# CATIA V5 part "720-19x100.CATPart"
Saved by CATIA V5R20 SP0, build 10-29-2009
Part number: 720-19x100
Definition: NONE
Nomenclature: 720-19x100
Source: Unknown
Description: 720-19x100
Bounding box of the stored display mesh (mm): x 0 to 100, y -9.5 to 9.5, z -9.5 to 9.5
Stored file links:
  C:\Users\Utente\Desktop\IO LAVORO\3D X SITO CF\X SITO\720\720-19x100.CATPart

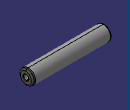
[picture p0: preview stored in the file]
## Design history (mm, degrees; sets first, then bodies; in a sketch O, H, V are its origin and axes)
Body1 "720-19x100" (main body)
  Solid1: solid without history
